VERSION 5.7 ;
  NOWIREEXTENSIONATPIN ON ;
  DIVIDERCHAR "/" ;
  BUSBITCHARS "[]" ;
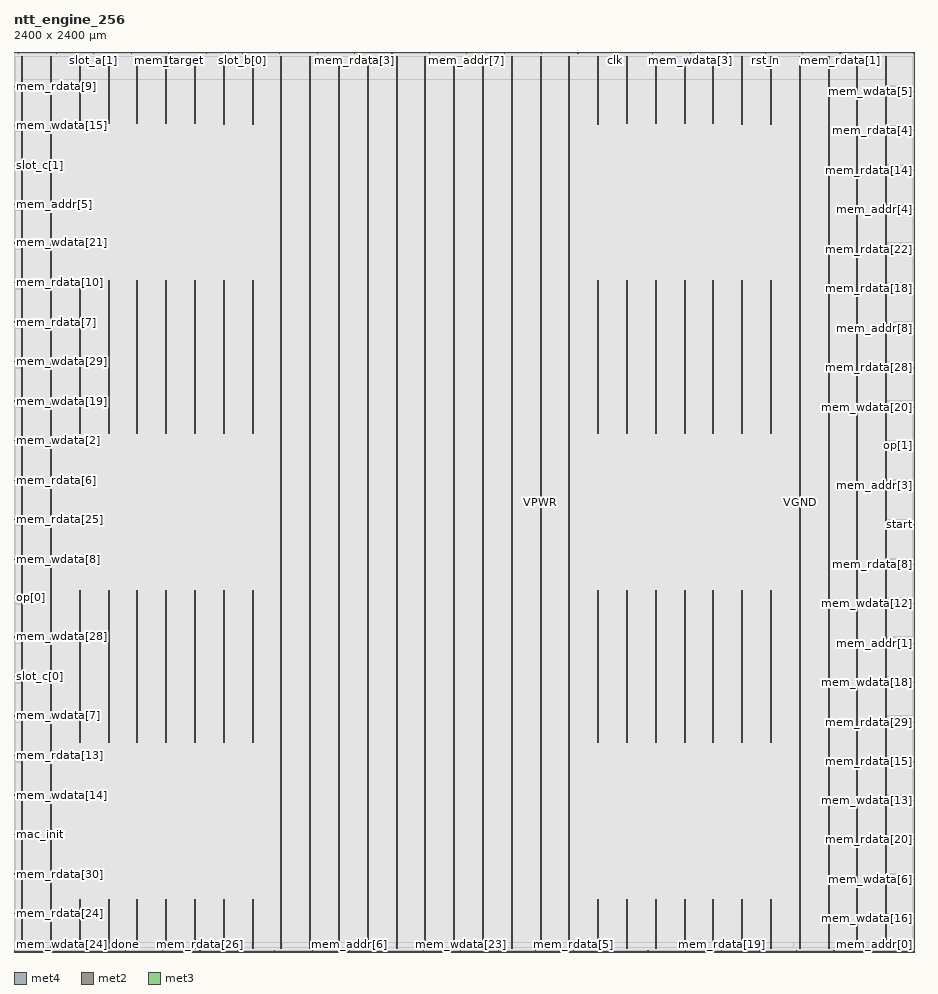
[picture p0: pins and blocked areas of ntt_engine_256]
MACRO ntt_engine_256
  CLASS BLOCK ;
  FOREIGN ntt_engine_256 ;
  ORIGIN 0.000 0.000 ;
  SIZE 2400.000 BY 2400.000 ;
  PIN VGND
    DIRECTION INOUT ;
    USE GROUND ;
    PORT
      LAYER met4 ;
        RECT 97.240 10.640 100.040 2388.400 ;
    END
    PORT
      LAYER met4 ;
        RECT 250.840 10.640 253.640 139.400 ;
    END
    PORT
      LAYER met4 ;
        RECT 250.840 557.480 253.640 964.400 ;
    END
    PORT
      LAYER met4 ;
        RECT 250.840 1382.480 253.640 1790.020 ;
    END
    PORT
      LAYER met4 ;
        RECT 250.840 2208.100 253.640 2388.400 ;
    END
    PORT
      LAYER met4 ;
        RECT 404.440 10.640 407.240 139.400 ;
    END
    PORT
      LAYER met4 ;
        RECT 404.440 557.480 407.240 964.400 ;
    END
    PORT
      LAYER met4 ;
        RECT 404.440 1382.480 407.240 1790.020 ;
    END
    PORT
      LAYER met4 ;
        RECT 404.440 2208.100 407.240 2388.400 ;
    END
    PORT
      LAYER met4 ;
        RECT 558.040 10.640 560.840 140.020 ;
    END
    PORT
      LAYER met4 ;
        RECT 558.040 557.480 560.840 965.020 ;
    END
    PORT
      LAYER met4 ;
        RECT 558.040 1382.480 560.840 1790.020 ;
    END
    PORT
      LAYER met4 ;
        RECT 558.040 2207.480 560.840 2388.400 ;
    END
    PORT
      LAYER met4 ;
        RECT 711.640 10.640 714.440 2388.400 ;
    END
    PORT
      LAYER met4 ;
        RECT 865.240 10.640 868.040 2388.400 ;
    END
    PORT
      LAYER met4 ;
        RECT 1018.840 10.640 1021.640 2388.400 ;
    END
    PORT
      LAYER met4 ;
        RECT 1172.440 10.640 1175.240 2388.400 ;
    END
    PORT
      LAYER met4 ;
        RECT 1326.040 10.640 1328.840 2388.400 ;
    END
    PORT
      LAYER met4 ;
        RECT 1479.640 10.640 1482.440 2388.400 ;
    END
    PORT
      LAYER met4 ;
        RECT 1633.240 10.640 1636.040 139.400 ;
    END
    PORT
      LAYER met4 ;
        RECT 1633.240 557.480 1636.040 964.400 ;
    END
    PORT
      LAYER met4 ;
        RECT 1633.240 1382.480 1636.040 1790.020 ;
    END
    PORT
      LAYER met4 ;
        RECT 1633.240 2208.100 1636.040 2388.400 ;
    END
    PORT
      LAYER met4 ;
        RECT 1786.840 10.640 1789.640 139.400 ;
    END
    PORT
      LAYER met4 ;
        RECT 1786.840 557.480 1789.640 964.400 ;
    END
    PORT
      LAYER met4 ;
        RECT 1786.840 1382.480 1789.640 1790.020 ;
    END
    PORT
      LAYER met4 ;
        RECT 1786.840 2208.100 1789.640 2388.400 ;
    END
    PORT
      LAYER met4 ;
        RECT 1940.440 10.640 1943.240 140.020 ;
    END
    PORT
      LAYER met4 ;
        RECT 1940.440 557.480 1943.240 965.020 ;
    END
    PORT
      LAYER met4 ;
        RECT 1940.440 1382.480 1943.240 1790.020 ;
    END
    PORT
      LAYER met4 ;
        RECT 1940.440 2207.480 1943.240 2388.400 ;
    END
    PORT
      LAYER met4 ;
        RECT 2094.040 10.640 2096.840 2388.400 ;
    END
    PORT
      LAYER met4 ;
        RECT 2247.640 10.640 2250.440 2388.400 ;
    END
  END VGND
  PIN VPWR
    DIRECTION INOUT ;
    USE POWER ;
    PORT
      LAYER met4 ;
        RECT 20.440 10.640 23.240 2388.400 ;
    END
    PORT
      LAYER met4 ;
        RECT 174.040 10.640 176.840 140.020 ;
    END
    PORT
      LAYER met4 ;
        RECT 174.040 557.360 176.840 965.020 ;
    END
    PORT
      LAYER met4 ;
        RECT 174.040 1382.480 176.840 1790.020 ;
    END
    PORT
      LAYER met4 ;
        RECT 174.040 2207.480 176.840 2388.400 ;
    END
    PORT
      LAYER met4 ;
        RECT 327.640 10.640 330.440 139.400 ;
    END
    PORT
      LAYER met4 ;
        RECT 327.640 558.100 330.440 964.400 ;
    END
    PORT
      LAYER met4 ;
        RECT 327.640 1383.100 330.440 1789.400 ;
    END
    PORT
      LAYER met4 ;
        RECT 327.640 2208.100 330.440 2388.400 ;
    END
    PORT
      LAYER met4 ;
        RECT 481.240 10.640 484.040 139.400 ;
    END
    PORT
      LAYER met4 ;
        RECT 481.240 558.100 484.040 964.400 ;
    END
    PORT
      LAYER met4 ;
        RECT 481.240 1383.100 484.040 1789.400 ;
    END
    PORT
      LAYER met4 ;
        RECT 481.240 2208.100 484.040 2388.400 ;
    END
    PORT
      LAYER met4 ;
        RECT 634.840 10.640 637.640 140.020 ;
    END
    PORT
      LAYER met4 ;
        RECT 634.840 557.360 637.640 965.020 ;
    END
    PORT
      LAYER met4 ;
        RECT 634.840 1382.480 637.640 1790.020 ;
    END
    PORT
      LAYER met4 ;
        RECT 634.840 2207.480 637.640 2388.400 ;
    END
    PORT
      LAYER met4 ;
        RECT 788.440 10.640 791.240 2388.400 ;
    END
    PORT
      LAYER met4 ;
        RECT 942.040 10.640 944.840 2388.400 ;
    END
    PORT
      LAYER met4 ;
        RECT 1095.640 10.640 1098.440 2388.400 ;
    END
    PORT
      LAYER met4 ;
        RECT 1249.240 10.640 1252.040 2388.400 ;
    END
    PORT
      LAYER met4 ;
        RECT 1402.840 10.640 1405.640 2388.400 ;
    END
    PORT
      LAYER met4 ;
        RECT 1556.440 10.640 1559.240 140.020 ;
    END
    PORT
      LAYER met4 ;
        RECT 1556.440 557.360 1559.240 965.020 ;
    END
    PORT
      LAYER met4 ;
        RECT 1556.440 1382.480 1559.240 1790.020 ;
    END
    PORT
      LAYER met4 ;
        RECT 1556.440 2207.480 1559.240 2388.400 ;
    END
    PORT
      LAYER met4 ;
        RECT 1710.040 10.640 1712.840 139.400 ;
    END
    PORT
      LAYER met4 ;
        RECT 1710.040 558.100 1712.840 964.400 ;
    END
    PORT
      LAYER met4 ;
        RECT 1710.040 1383.100 1712.840 1789.400 ;
    END
    PORT
      LAYER met4 ;
        RECT 1710.040 2208.100 1712.840 2388.400 ;
    END
    PORT
      LAYER met4 ;
        RECT 1863.640 10.640 1866.440 139.400 ;
    END
    PORT
      LAYER met4 ;
        RECT 1863.640 558.100 1866.440 964.400 ;
    END
    PORT
      LAYER met4 ;
        RECT 1863.640 1383.100 1866.440 1789.400 ;
    END
    PORT
      LAYER met4 ;
        RECT 1863.640 2208.100 1866.440 2388.400 ;
    END
    PORT
      LAYER met4 ;
        RECT 2017.240 10.640 2020.040 140.020 ;
    END
    PORT
      LAYER met4 ;
        RECT 2017.240 557.360 2020.040 965.020 ;
    END
    PORT
      LAYER met4 ;
        RECT 2017.240 1382.480 2020.040 1790.020 ;
    END
    PORT
      LAYER met4 ;
        RECT 2017.240 2207.480 2020.040 2388.400 ;
    END
    PORT
      LAYER met4 ;
        RECT 2170.840 10.640 2173.640 2388.400 ;
    END
    PORT
      LAYER met4 ;
        RECT 2324.440 10.640 2327.240 2388.400 ;
    END
  END VPWR
  PIN busy
    DIRECTION OUTPUT TRISTATE ;
    USE SIGNAL ;
    ANTENNADIFFAREA 1.782000 ;
    PORT
      LAYER met2 ;
        RECT 808.310 2396.000 808.590 2400.000 ;
    END
  END busy
  PIN clk
    DIRECTION INPUT ;
    USE SIGNAL ;
    ANTENNAGATEAREA 0.852000 ;
    ANTENNADIFFAREA 1.304100 ;
    PORT
      LAYER met2 ;
        RECT 1603.650 2396.000 1603.930 2400.000 ;
    END
  END clk
  PIN done
    DIRECTION OUTPUT TRISTATE ;
    USE SIGNAL ;
    ANTENNADIFFAREA 1.782000 ;
    PORT
      LAYER met2 ;
        RECT 296.330 0.000 296.610 4.000 ;
    END
  END done
  PIN mac_init
    DIRECTION INPUT ;
    USE SIGNAL ;
    ANTENNAGATEAREA 0.213000 ;
    PORT
      LAYER met3 ;
        RECT 0.000 312.840 4.000 313.440 ;
    END
  END mac_init
  PIN mem_addr[0]
    DIRECTION INPUT ;
    USE SIGNAL ;
    ANTENNAGATEAREA 0.495000 ;
    PORT
      LAYER met2 ;
        RECT 2386.110 0.000 2386.390 4.000 ;
    END
  END mem_addr[0]
  PIN mem_addr[1]
    DIRECTION INPUT ;
    USE SIGNAL ;
    ANTENNAGATEAREA 0.196500 ;
    PORT
      LAYER met3 ;
        RECT 2396.000 822.840 2400.000 823.440 ;
    END
  END mem_addr[1]
  PIN mem_addr[2]
    DIRECTION INPUT ;
    USE SIGNAL ;
    ANTENNAGATEAREA 0.495000 ;
    PORT
      LAYER met2 ;
        RECT 2102.750 2396.000 2103.030 2400.000 ;
    END
  END mem_addr[2]
  PIN mem_addr[3]
    DIRECTION INPUT ;
    USE SIGNAL ;
    ANTENNAGATEAREA 0.196500 ;
    PORT
      LAYER met3 ;
        RECT 2396.000 1244.440 2400.000 1245.040 ;
    END
  END mem_addr[3]
  PIN mem_addr[4]
    DIRECTION INPUT ;
    USE SIGNAL ;
    ANTENNAGATEAREA 0.495000 ;
    PORT
      LAYER met3 ;
        RECT 2396.000 1978.840 2400.000 1979.440 ;
    END
  END mem_addr[4]
  PIN mem_addr[5]
    DIRECTION INPUT ;
    USE SIGNAL ;
    ANTENNAGATEAREA 0.495000 ;
    PORT
      LAYER met3 ;
        RECT 0.000 1992.440 4.000 1993.040 ;
    END
  END mem_addr[5]
  PIN mem_addr[6]
    DIRECTION INPUT ;
    USE SIGNAL ;
    ANTENNAGATEAREA 0.495000 ;
    PORT
      LAYER met2 ;
        RECT 895.250 0.000 895.530 4.000 ;
    END
  END mem_addr[6]
  PIN mem_addr[7]
    DIRECTION INPUT ;
    USE SIGNAL ;
    ANTENNAGATEAREA 0.495000 ;
    PORT
      LAYER met2 ;
        RECT 1207.590 2396.000 1207.870 2400.000 ;
    END
  END mem_addr[7]
  PIN mem_addr[8]
    DIRECTION INPUT ;
    USE SIGNAL ;
    ANTENNAGATEAREA 0.495000 ;
    PORT
      LAYER met3 ;
        RECT 2396.000 1662.640 2400.000 1663.240 ;
    END
  END mem_addr[8]
  PIN mem_rdata[0]
    DIRECTION OUTPUT TRISTATE ;
    USE SIGNAL ;
    ANTENNADIFFAREA 1.782000 ;
    PORT
      LAYER met2 ;
        RECT 2286.290 0.000 2286.570 4.000 ;
    END
  END mem_rdata[0]
  PIN mem_rdata[10]
    DIRECTION OUTPUT TRISTATE ;
    USE SIGNAL ;
    ANTENNADIFFAREA 1.782000 ;
    PORT
      LAYER met3 ;
        RECT 0.000 1785.040 4.000 1785.640 ;
    END
  END mem_rdata[10]
  PIN mem_rdata[11]
    DIRECTION OUTPUT TRISTATE ;
    USE SIGNAL ;
    ANTENNADIFFAREA 1.782000 ;
    PORT
      LAYER met2 ;
        RECT 112.790 2396.000 113.070 2400.000 ;
    END
  END mem_rdata[11]
  PIN mem_rdata[12]
    DIRECTION OUTPUT TRISTATE ;
    USE SIGNAL ;
    ANTENNADIFFAREA 1.782000 ;
    PORT
      LAYER met2 ;
        RECT 1007.950 2396.000 1008.230 2400.000 ;
    END
  END mem_rdata[12]
  PIN mem_rdata[13]
    DIRECTION OUTPUT TRISTATE ;
    USE SIGNAL ;
    ANTENNADIFFAREA 1.782000 ;
    PORT
      LAYER met3 ;
        RECT 0.000 523.640 4.000 524.240 ;
    END
  END mem_rdata[13]
  PIN mem_rdata[14]
    DIRECTION OUTPUT TRISTATE ;
    USE SIGNAL ;
    ANTENNADIFFAREA 1.782000 ;
    PORT
      LAYER met3 ;
        RECT 2396.000 2084.240 2400.000 2084.840 ;
    END
  END mem_rdata[14]
  PIN mem_rdata[15]
    DIRECTION OUTPUT TRISTATE ;
    USE SIGNAL ;
    ANTENNADIFFAREA 1.782000 ;
    PORT
      LAYER met3 ;
        RECT 2396.000 506.640 2400.000 507.240 ;
    END
  END mem_rdata[15]
  PIN mem_rdata[16]
    DIRECTION OUTPUT TRISTATE ;
    USE SIGNAL ;
    ANTENNADIFFAREA 1.782000 ;
    PORT
      LAYER met2 ;
        RECT 1703.470 2396.000 1703.750 2400.000 ;
    END
  END mem_rdata[16]
  PIN mem_rdata[17]
    DIRECTION OUTPUT TRISTATE ;
    USE SIGNAL ;
    ANTENNADIFFAREA 1.782000 ;
    PORT
      LAYER met2 ;
        RECT 595.790 0.000 596.070 4.000 ;
    END
  END mem_rdata[17]
  PIN mem_rdata[18]
    DIRECTION OUTPUT TRISTATE ;
    USE SIGNAL ;
    ANTENNADIFFAREA 1.782000 ;
    PORT
      LAYER met3 ;
        RECT 2396.000 1768.040 2400.000 1768.640 ;
    END
  END mem_rdata[18]
  PIN mem_rdata[19]
    DIRECTION OUTPUT TRISTATE ;
    USE SIGNAL ;
    ANTENNADIFFAREA 1.782000 ;
    PORT
      LAYER met2 ;
        RECT 1887.010 0.000 1887.290 4.000 ;
    END
  END mem_rdata[19]
  PIN mem_rdata[1]
    DIRECTION OUTPUT TRISTATE ;
    USE SIGNAL ;
    ANTENNADIFFAREA 1.782000 ;
    PORT
      LAYER met2 ;
        RECT 2202.570 2396.000 2202.850 2400.000 ;
    END
  END mem_rdata[1]
  PIN mem_rdata[20]
    DIRECTION OUTPUT TRISTATE ;
    USE SIGNAL ;
    ANTENNADIFFAREA 1.782000 ;
    PORT
      LAYER met3 ;
        RECT 2396.000 299.240 2400.000 299.840 ;
    END
  END mem_rdata[20]
  PIN mem_rdata[21]
    DIRECTION OUTPUT TRISTATE ;
    USE SIGNAL ;
    ANTENNADIFFAREA 1.782000 ;
    PORT
      LAYER met2 ;
        RECT 1407.230 2396.000 1407.510 2400.000 ;
    END
  END mem_rdata[21]
  PIN mem_rdata[22]
    DIRECTION OUTPUT TRISTATE ;
    USE SIGNAL ;
    ANTENNADIFFAREA 1.782000 ;
    PORT
      LAYER met3 ;
        RECT 2396.000 1873.440 2400.000 1874.040 ;
    END
  END mem_rdata[22]
  PIN mem_rdata[23]
    DIRECTION OUTPUT TRISTATE ;
    USE SIGNAL ;
    ANTENNADIFFAREA 1.782000 ;
    PORT
      LAYER met2 ;
        RECT 12.970 2396.000 13.250 2400.000 ;
    END
  END mem_rdata[23]
  PIN mem_rdata[24]
    DIRECTION OUTPUT TRISTATE ;
    USE SIGNAL ;
    ANTENNADIFFAREA 1.782000 ;
    PORT
      LAYER met3 ;
        RECT 0.000 102.040 4.000 102.640 ;
    END
  END mem_rdata[24]
  PIN mem_rdata[25]
    DIRECTION OUTPUT TRISTATE ;
    USE SIGNAL ;
    ANTENNADIFFAREA 1.782000 ;
    PORT
      LAYER met3 ;
        RECT 0.000 1152.640 4.000 1153.240 ;
    END
  END mem_rdata[25]
  PIN mem_rdata[26]
    DIRECTION OUTPUT TRISTATE ;
    USE SIGNAL ;
    ANTENNADIFFAREA 1.782000 ;
    PORT
      LAYER met2 ;
        RECT 495.970 0.000 496.250 4.000 ;
    END
  END mem_rdata[26]
  PIN mem_rdata[27]
    DIRECTION OUTPUT TRISTATE ;
    USE SIGNAL ;
    ANTENNADIFFAREA 1.782000 ;
    PORT
      LAYER met2 ;
        RECT 1107.770 2396.000 1108.050 2400.000 ;
    END
  END mem_rdata[27]
  PIN mem_rdata[28]
    DIRECTION OUTPUT TRISTATE ;
    USE SIGNAL ;
    ANTENNADIFFAREA 1.782000 ;
    PORT
      LAYER met3 ;
        RECT 2396.000 1557.240 2400.000 1557.840 ;
    END
  END mem_rdata[28]
  PIN mem_rdata[29]
    DIRECTION OUTPUT TRISTATE ;
    USE SIGNAL ;
    ANTENNADIFFAREA 1.782000 ;
    PORT
      LAYER met3 ;
        RECT 2396.000 612.040 2400.000 612.640 ;
    END
  END mem_rdata[29]
  PIN mem_rdata[2]
    DIRECTION OUTPUT TRISTATE ;
    USE SIGNAL ;
    ANTENNADIFFAREA 1.782000 ;
    PORT
      LAYER met2 ;
        RECT 1503.830 2396.000 1504.110 2400.000 ;
    END
  END mem_rdata[2]
  PIN mem_rdata[30]
    DIRECTION OUTPUT TRISTATE ;
    USE SIGNAL ;
    ANTENNADIFFAREA 1.782000 ;
    PORT
      LAYER met3 ;
        RECT 0.000 207.440 4.000 208.040 ;
    END
  END mem_rdata[30]
  PIN mem_rdata[31]
    DIRECTION OUTPUT TRISTATE ;
    USE SIGNAL ;
    ANTENNADIFFAREA 1.782000 ;
    PORT
      LAYER met2 ;
        RECT 2186.470 0.000 2186.750 4.000 ;
    END
  END mem_rdata[31]
  PIN mem_rdata[3]
    DIRECTION OUTPUT TRISTATE ;
    USE SIGNAL ;
    ANTENNADIFFAREA 1.782000 ;
    PORT
      LAYER met2 ;
        RECT 908.130 2396.000 908.410 2400.000 ;
    END
  END mem_rdata[3]
  PIN mem_rdata[4]
    DIRECTION OUTPUT TRISTATE ;
    USE SIGNAL ;
    ANTENNADIFFAREA 1.782000 ;
    PORT
      LAYER met3 ;
        RECT 2396.000 2189.640 2400.000 2190.240 ;
    END
  END mem_rdata[4]
  PIN mem_rdata[5]
    DIRECTION OUTPUT TRISTATE ;
    USE SIGNAL ;
    ANTENNADIFFAREA 1.782000 ;
    PORT
      LAYER met2 ;
        RECT 1490.950 0.000 1491.230 4.000 ;
    END
  END mem_rdata[5]
  PIN mem_rdata[6]
    DIRECTION OUTPUT TRISTATE ;
    USE SIGNAL ;
    ANTENNADIFFAREA 1.782000 ;
    PORT
      LAYER met3 ;
        RECT 0.000 1258.040 4.000 1258.640 ;
    END
  END mem_rdata[6]
  PIN mem_rdata[7]
    DIRECTION OUTPUT TRISTATE ;
    USE SIGNAL ;
    ANTENNADIFFAREA 1.782000 ;
    PORT
      LAYER met3 ;
        RECT 0.000 1679.640 4.000 1680.240 ;
    END
  END mem_rdata[7]
  PIN mem_rdata[8]
    DIRECTION OUTPUT TRISTATE ;
    USE SIGNAL ;
    ANTENNADIFFAREA 1.782000 ;
    PORT
      LAYER met3 ;
        RECT 2396.000 1033.640 2400.000 1034.240 ;
    END
  END mem_rdata[8]
  PIN mem_rdata[9]
    DIRECTION OUTPUT TRISTATE ;
    USE SIGNAL ;
    ANTENNADIFFAREA 1.782000 ;
    PORT
      LAYER met3 ;
        RECT 0.000 2308.640 4.000 2309.240 ;
    END
  END mem_rdata[9]
  PIN mem_re
    DIRECTION INPUT ;
    USE SIGNAL ;
    ANTENNAGATEAREA 0.495000 ;
    PORT
      LAYER met2 ;
        RECT 1986.830 0.000 1987.110 4.000 ;
    END
  END mem_re
  PIN mem_rvalid
    DIRECTION OUTPUT TRISTATE ;
    USE SIGNAL ;
    ANTENNADIFFAREA 1.782000 ;
    PORT
      LAYER met2 ;
        RECT 991.850 0.000 992.130 4.000 ;
    END
  END mem_rvalid
  PIN mem_slot[0]
    DIRECTION INPUT ;
    USE SIGNAL ;
    ANTENNAGATEAREA 0.196500 ;
    PORT
      LAYER met2 ;
        RECT 1690.590 0.000 1690.870 4.000 ;
    END
  END mem_slot[0]
  PIN mem_slot[1]
    DIRECTION INPUT ;
    USE SIGNAL ;
    ANTENNAGATEAREA 0.196500 ;
    PORT
      LAYER met2 ;
        RECT 2398.990 2396.000 2399.270 2400.000 ;
    END
  END mem_slot[1]
  PIN mem_target
    DIRECTION INPUT ;
    USE SIGNAL ;
    ANTENNAGATEAREA 0.495000 ;
    PORT
      LAYER met2 ;
        RECT 412.250 2396.000 412.530 2400.000 ;
    END
  END mem_target
  PIN mem_wdata[0]
    DIRECTION INPUT ;
    USE SIGNAL ;
    ANTENNAGATEAREA 0.196500 ;
    PORT
      LAYER met2 ;
        RECT 196.510 0.000 196.790 4.000 ;
    END
  END mem_wdata[0]
  PIN mem_wdata[10]
    DIRECTION INPUT ;
    USE SIGNAL ;
    ANTENNAGATEAREA 0.495000 ;
    PORT
      LAYER met2 ;
        RECT 695.610 0.000 695.890 4.000 ;
    END
  END mem_wdata[10]
  PIN mem_wdata[11]
    DIRECTION INPUT ;
    USE SIGNAL ;
    ANTENNAGATEAREA 0.495000 ;
    PORT
      LAYER met2 ;
        RECT 2086.650 0.000 2086.930 4.000 ;
    END
  END mem_wdata[11]
  PIN mem_wdata[12]
    DIRECTION INPUT ;
    USE SIGNAL ;
    ANTENNAGATEAREA 0.126000 ;
    PORT
      LAYER met3 ;
        RECT 2396.000 928.240 2400.000 928.840 ;
    END
  END mem_wdata[12]
  PIN mem_wdata[13]
    DIRECTION INPUT ;
    USE SIGNAL ;
    ANTENNAGATEAREA 0.495000 ;
    PORT
      LAYER met3 ;
        RECT 2396.000 404.640 2400.000 405.240 ;
    END
  END mem_wdata[13]
  PIN mem_wdata[14]
    DIRECTION INPUT ;
    USE SIGNAL ;
    ANTENNAGATEAREA 0.495000 ;
    PORT
      LAYER met3 ;
        RECT 0.000 418.240 4.000 418.840 ;
    END
  END mem_wdata[14]
  PIN mem_wdata[15]
    DIRECTION INPUT ;
    USE SIGNAL ;
    ANTENNAGATEAREA 0.495000 ;
    PORT
      LAYER met3 ;
        RECT 0.000 2203.240 4.000 2203.840 ;
    END
  END mem_wdata[15]
  PIN mem_wdata[16]
    DIRECTION INPUT ;
    USE SIGNAL ;
    ANTENNAGATEAREA 0.495000 ;
    PORT
      LAYER met3 ;
        RECT 2396.000 88.440 2400.000 89.040 ;
    END
  END mem_wdata[16]
  PIN mem_wdata[17]
    DIRECTION INPUT ;
    USE SIGNAL ;
    ANTENNAGATEAREA 0.495000 ;
    PORT
      LAYER met2 ;
        RECT 512.070 2396.000 512.350 2400.000 ;
    END
  END mem_wdata[17]
  PIN mem_wdata[18]
    DIRECTION INPUT ;
    USE SIGNAL ;
    ANTENNAGATEAREA 0.126000 ;
    ANTENNADIFFAREA 0.434700 ;
    PORT
      LAYER met3 ;
        RECT 2396.000 717.440 2400.000 718.040 ;
    END
  END mem_wdata[18]
  PIN mem_wdata[19]
    DIRECTION INPUT ;
    USE SIGNAL ;
    ANTENNAGATEAREA 0.495000 ;
    PORT
      LAYER met3 ;
        RECT 0.000 1468.840 4.000 1469.440 ;
    END
  END mem_wdata[19]
  PIN mem_wdata[1]
    DIRECTION INPUT ;
    USE SIGNAL ;
    ANTENNAGATEAREA 0.495000 ;
    PORT
      LAYER met2 ;
        RECT 1790.410 0.000 1790.690 4.000 ;
    END
  END mem_wdata[1]
  PIN mem_wdata[20]
    DIRECTION INPUT ;
    USE SIGNAL ;
    ANTENNAGATEAREA 0.196500 ;
    PORT
      LAYER met3 ;
        RECT 2396.000 1451.840 2400.000 1452.440 ;
    END
  END mem_wdata[20]
  PIN mem_wdata[21]
    DIRECTION INPUT ;
    USE SIGNAL ;
    ANTENNAGATEAREA 0.495000 ;
    PORT
      LAYER met3 ;
        RECT 0.000 1890.440 4.000 1891.040 ;
    END
  END mem_wdata[21]
  PIN mem_wdata[22]
    DIRECTION INPUT ;
    USE SIGNAL ;
    ANTENNAGATEAREA 0.196500 ;
    PORT
      LAYER met2 ;
        RECT 312.430 2396.000 312.710 2400.000 ;
    END
  END mem_wdata[22]
  PIN mem_wdata[23]
    DIRECTION INPUT ;
    USE SIGNAL ;
    ANTENNAGATEAREA 0.495000 ;
    PORT
      LAYER met2 ;
        RECT 1191.490 0.000 1191.770 4.000 ;
    END
  END mem_wdata[23]
  PIN mem_wdata[24]
    DIRECTION INPUT ;
    USE SIGNAL ;
    ANTENNAGATEAREA 0.495000 ;
    PORT
      LAYER met2 ;
        RECT 0.090 0.000 0.370 4.000 ;
    END
  END mem_wdata[24]
  PIN mem_wdata[25]
    DIRECTION INPUT ;
    USE SIGNAL ;
    ANTENNAGATEAREA 0.495000 ;
    PORT
      LAYER met2 ;
        RECT 1391.130 0.000 1391.410 4.000 ;
    END
  END mem_wdata[25]
  PIN mem_wdata[26]
    DIRECTION INPUT ;
    USE SIGNAL ;
    ANTENNAGATEAREA 0.495000 ;
    PORT
      LAYER met2 ;
        RECT 708.490 2396.000 708.770 2400.000 ;
    END
  END mem_wdata[26]
  PIN mem_wdata[27]
    DIRECTION INPUT ;
    USE SIGNAL ;
    ANTENNAGATEAREA 0.495000 ;
    PORT
      LAYER met2 ;
        RECT 1307.410 2396.000 1307.690 2400.000 ;
    END
  END mem_wdata[27]
  PIN mem_wdata[28]
    DIRECTION INPUT ;
    USE SIGNAL ;
    ANTENNAGATEAREA 0.196500 ;
    PORT
      LAYER met3 ;
        RECT 0.000 839.840 4.000 840.440 ;
    END
  END mem_wdata[28]
  PIN mem_wdata[29]
    DIRECTION INPUT ;
    USE SIGNAL ;
    ANTENNAGATEAREA 0.196500 ;
    PORT
      LAYER met3 ;
        RECT 0.000 1574.240 4.000 1574.840 ;
    END
  END mem_wdata[29]
  PIN mem_wdata[2]
    DIRECTION INPUT ;
    USE SIGNAL ;
    ANTENNAGATEAREA 0.495000 ;
    PORT
      LAYER met3 ;
        RECT 0.000 1363.440 4.000 1364.040 ;
    END
  END mem_wdata[2]
  PIN mem_wdata[30]
    DIRECTION INPUT ;
    USE SIGNAL ;
    ANTENNAGATEAREA 0.495000 ;
    PORT
      LAYER met2 ;
        RECT 96.690 0.000 96.970 4.000 ;
    END
  END mem_wdata[30]
  PIN mem_wdata[31]
    DIRECTION INPUT ;
    USE SIGNAL ;
    ANTENNAGATEAREA 0.495000 ;
    PORT
      LAYER met2 ;
        RECT 2302.390 2396.000 2302.670 2400.000 ;
    END
  END mem_wdata[31]
  PIN mem_wdata[3]
    DIRECTION INPUT ;
    USE SIGNAL ;
    ANTENNAGATEAREA 0.495000 ;
    PORT
      LAYER met2 ;
        RECT 1803.290 2396.000 1803.570 2400.000 ;
    END
  END mem_wdata[3]
  PIN mem_wdata[4]
    DIRECTION INPUT ;
    USE SIGNAL ;
    ANTENNAGATEAREA 0.495000 ;
    PORT
      LAYER met2 ;
        RECT 1091.670 0.000 1091.950 4.000 ;
    END
  END mem_wdata[4]
  PIN mem_wdata[5]
    DIRECTION INPUT ;
    USE SIGNAL ;
    ANTENNAGATEAREA 0.213000 ;
    PORT
      LAYER met3 ;
        RECT 2396.000 2295.040 2400.000 2295.640 ;
    END
  END mem_wdata[5]
  PIN mem_wdata[6]
    DIRECTION INPUT ;
    USE SIGNAL ;
    ANTENNAGATEAREA 0.196500 ;
    PORT
      LAYER met3 ;
        RECT 2396.000 193.840 2400.000 194.440 ;
    END
  END mem_wdata[6]
  PIN mem_wdata[7]
    DIRECTION INPUT ;
    USE SIGNAL ;
    ANTENNAGATEAREA 0.495000 ;
    PORT
      LAYER met3 ;
        RECT 0.000 629.040 4.000 629.640 ;
    END
  END mem_wdata[7]
  PIN mem_wdata[8]
    DIRECTION INPUT ;
    USE SIGNAL ;
    ANTENNAGATEAREA 0.126000 ;
    PORT
      LAYER met3 ;
        RECT 0.000 1047.240 4.000 1047.840 ;
    END
  END mem_wdata[8]
  PIN mem_wdata[9]
    DIRECTION INPUT ;
    USE SIGNAL ;
    ANTENNAGATEAREA 0.742500 ;
    PORT
      LAYER met2 ;
        RECT 396.150 0.000 396.430 4.000 ;
    END
  END mem_wdata[9]
  PIN mem_we
    DIRECTION INPUT ;
    USE SIGNAL ;
    ANTENNAGATEAREA 0.495000 ;
    PORT
      LAYER met2 ;
        RECT 795.430 0.000 795.710 4.000 ;
    END
  END mem_we
  PIN op[0]
    DIRECTION INPUT ;
    USE SIGNAL ;
    ANTENNAGATEAREA 0.247500 ;
    PORT
      LAYER met3 ;
        RECT 0.000 945.240 4.000 945.840 ;
    END
  END op[0]
  PIN op[1]
    DIRECTION INPUT ;
    USE SIGNAL ;
    ANTENNAGATEAREA 0.495000 ;
    PORT
      LAYER met3 ;
        RECT 2396.000 1349.840 2400.000 1350.440 ;
    END
  END op[1]
  PIN op[2]
    DIRECTION INPUT ;
    USE SIGNAL ;
    ANTENNAGATEAREA 0.495000 ;
    PORT
      LAYER met2 ;
        RECT 1291.310 0.000 1291.590 4.000 ;
    END
  END op[2]
  PIN rst_n
    DIRECTION INPUT ;
    USE SIGNAL ;
    ANTENNAGATEAREA 0.196500 ;
    PORT
      LAYER met2 ;
        RECT 2002.930 2396.000 2003.210 2400.000 ;
    END
  END rst_n
  PIN slot_a[0]
    DIRECTION INPUT ;
    USE SIGNAL ;
    ANTENNAGATEAREA 0.495000 ;
    PORT
      LAYER met2 ;
        RECT 1903.110 2396.000 1903.390 2400.000 ;
    END
  END slot_a[0]
  PIN slot_a[1]
    DIRECTION INPUT ;
    USE SIGNAL ;
    ANTENNAGATEAREA 0.495000 ;
    PORT
      LAYER met2 ;
        RECT 212.610 2396.000 212.890 2400.000 ;
    END
  END slot_a[1]
  PIN slot_b[0]
    DIRECTION INPUT ;
    USE SIGNAL ;
    ANTENNAGATEAREA 0.495000 ;
    PORT
      LAYER met2 ;
        RECT 608.670 2396.000 608.950 2400.000 ;
    END
  END slot_b[0]
  PIN slot_b[1]
    DIRECTION INPUT ;
    USE SIGNAL ;
    ANTENNAGATEAREA 0.495000 ;
    PORT
      LAYER met2 ;
        RECT 1590.770 0.000 1591.050 4.000 ;
    END
  END slot_b[1]
  PIN slot_c[0]
    DIRECTION INPUT ;
    USE SIGNAL ;
    ANTENNAGATEAREA 0.495000 ;
    PORT
      LAYER met3 ;
        RECT 0.000 734.440 4.000 735.040 ;
    END
  END slot_c[0]
  PIN slot_c[1]
    DIRECTION INPUT ;
    USE SIGNAL ;
    ANTENNAGATEAREA 0.495000 ;
    PORT
      LAYER met3 ;
        RECT 0.000 2097.840 4.000 2098.440 ;
    END
  END slot_c[1]
  PIN start
    DIRECTION INPUT ;
    USE SIGNAL ;
    ANTENNAGATEAREA 0.495000 ;
    PORT
      LAYER met3 ;
        RECT 2396.000 1139.040 2400.000 1139.640 ;
    END
  END start
  OBS
      LAYER li1 ;
        RECT 5.520 10.795 2394.300 2388.245 ;
      LAYER met1 ;
        RECT 0.070 10.640 2399.290 2388.400 ;
      LAYER met2 ;
        RECT 0.100 2395.720 12.690 2396.730 ;
        RECT 13.530 2395.720 112.510 2396.730 ;
        RECT 113.350 2395.720 212.330 2396.730 ;
        RECT 213.170 2395.720 312.150 2396.730 ;
        RECT 312.990 2395.720 411.970 2396.730 ;
        RECT 412.810 2395.720 511.790 2396.730 ;
        RECT 512.630 2395.720 608.390 2396.730 ;
        RECT 609.230 2395.720 708.210 2396.730 ;
        RECT 709.050 2395.720 808.030 2396.730 ;
        RECT 808.870 2395.720 907.850 2396.730 ;
        RECT 908.690 2395.720 1007.670 2396.730 ;
        RECT 1008.510 2395.720 1107.490 2396.730 ;
        RECT 1108.330 2395.720 1207.310 2396.730 ;
        RECT 1208.150 2395.720 1307.130 2396.730 ;
        RECT 1307.970 2395.720 1406.950 2396.730 ;
        RECT 1407.790 2395.720 1503.550 2396.730 ;
        RECT 1504.390 2395.720 1603.370 2396.730 ;
        RECT 1604.210 2395.720 1703.190 2396.730 ;
        RECT 1704.030 2395.720 1803.010 2396.730 ;
        RECT 1803.850 2395.720 1902.830 2396.730 ;
        RECT 1903.670 2395.720 2002.650 2396.730 ;
        RECT 2003.490 2395.720 2102.470 2396.730 ;
        RECT 2103.310 2395.720 2202.290 2396.730 ;
        RECT 2203.130 2395.720 2302.110 2396.730 ;
        RECT 2302.950 2395.720 2398.710 2396.730 ;
        RECT 0.100 4.280 2399.260 2395.720 ;
        RECT 0.650 3.670 96.410 4.280 ;
        RECT 97.250 3.670 196.230 4.280 ;
        RECT 197.070 3.670 296.050 4.280 ;
        RECT 296.890 3.670 395.870 4.280 ;
        RECT 396.710 3.670 495.690 4.280 ;
        RECT 496.530 3.670 595.510 4.280 ;
        RECT 596.350 3.670 695.330 4.280 ;
        RECT 696.170 3.670 795.150 4.280 ;
        RECT 795.990 3.670 894.970 4.280 ;
        RECT 895.810 3.670 991.570 4.280 ;
        RECT 992.410 3.670 1091.390 4.280 ;
        RECT 1092.230 3.670 1191.210 4.280 ;
        RECT 1192.050 3.670 1291.030 4.280 ;
        RECT 1291.870 3.670 1390.850 4.280 ;
        RECT 1391.690 3.670 1490.670 4.280 ;
        RECT 1491.510 3.670 1590.490 4.280 ;
        RECT 1591.330 3.670 1690.310 4.280 ;
        RECT 1691.150 3.670 1790.130 4.280 ;
        RECT 1790.970 3.670 1886.730 4.280 ;
        RECT 1887.570 3.670 1986.550 4.280 ;
        RECT 1987.390 3.670 2086.370 4.280 ;
        RECT 2087.210 3.670 2186.190 4.280 ;
        RECT 2187.030 3.670 2286.010 4.280 ;
        RECT 2286.850 3.670 2385.830 4.280 ;
        RECT 2386.670 3.670 2399.260 4.280 ;
      LAYER met3 ;
        RECT 3.990 2309.640 2396.000 2388.325 ;
        RECT 4.400 2308.240 2396.000 2309.640 ;
        RECT 3.990 2296.040 2396.000 2308.240 ;
        RECT 3.990 2294.640 2395.600 2296.040 ;
        RECT 3.990 2204.240 2396.000 2294.640 ;
        RECT 4.400 2202.840 2396.000 2204.240 ;
        RECT 3.990 2190.640 2396.000 2202.840 ;
        RECT 3.990 2189.240 2395.600 2190.640 ;
        RECT 3.990 2098.840 2396.000 2189.240 ;
        RECT 4.400 2097.440 2396.000 2098.840 ;
        RECT 3.990 2085.240 2396.000 2097.440 ;
        RECT 3.990 2083.840 2395.600 2085.240 ;
        RECT 3.990 1993.440 2396.000 2083.840 ;
        RECT 4.400 1992.040 2396.000 1993.440 ;
        RECT 3.990 1979.840 2396.000 1992.040 ;
        RECT 3.990 1978.440 2395.600 1979.840 ;
        RECT 3.990 1891.440 2396.000 1978.440 ;
        RECT 4.400 1890.040 2396.000 1891.440 ;
        RECT 3.990 1874.440 2396.000 1890.040 ;
        RECT 3.990 1873.040 2395.600 1874.440 ;
        RECT 3.990 1786.040 2396.000 1873.040 ;
        RECT 4.400 1784.640 2396.000 1786.040 ;
        RECT 3.990 1769.040 2396.000 1784.640 ;
        RECT 3.990 1767.640 2395.600 1769.040 ;
        RECT 3.990 1680.640 2396.000 1767.640 ;
        RECT 4.400 1679.240 2396.000 1680.640 ;
        RECT 3.990 1663.640 2396.000 1679.240 ;
        RECT 3.990 1662.240 2395.600 1663.640 ;
        RECT 3.990 1575.240 2396.000 1662.240 ;
        RECT 4.400 1573.840 2396.000 1575.240 ;
        RECT 3.990 1558.240 2396.000 1573.840 ;
        RECT 3.990 1556.840 2395.600 1558.240 ;
        RECT 3.990 1469.840 2396.000 1556.840 ;
        RECT 4.400 1468.440 2396.000 1469.840 ;
        RECT 3.990 1452.840 2396.000 1468.440 ;
        RECT 3.990 1451.440 2395.600 1452.840 ;
        RECT 3.990 1364.440 2396.000 1451.440 ;
        RECT 4.400 1363.040 2396.000 1364.440 ;
        RECT 3.990 1350.840 2396.000 1363.040 ;
        RECT 3.990 1349.440 2395.600 1350.840 ;
        RECT 3.990 1259.040 2396.000 1349.440 ;
        RECT 4.400 1257.640 2396.000 1259.040 ;
        RECT 3.990 1245.440 2396.000 1257.640 ;
        RECT 3.990 1244.040 2395.600 1245.440 ;
        RECT 3.990 1153.640 2396.000 1244.040 ;
        RECT 4.400 1152.240 2396.000 1153.640 ;
        RECT 3.990 1140.040 2396.000 1152.240 ;
        RECT 3.990 1138.640 2395.600 1140.040 ;
        RECT 3.990 1048.240 2396.000 1138.640 ;
        RECT 4.400 1046.840 2396.000 1048.240 ;
        RECT 3.990 1034.640 2396.000 1046.840 ;
        RECT 3.990 1033.240 2395.600 1034.640 ;
        RECT 3.990 946.240 2396.000 1033.240 ;
        RECT 4.400 944.840 2396.000 946.240 ;
        RECT 3.990 929.240 2396.000 944.840 ;
        RECT 3.990 927.840 2395.600 929.240 ;
        RECT 3.990 840.840 2396.000 927.840 ;
        RECT 4.400 839.440 2396.000 840.840 ;
        RECT 3.990 823.840 2396.000 839.440 ;
        RECT 3.990 822.440 2395.600 823.840 ;
        RECT 3.990 735.440 2396.000 822.440 ;
        RECT 4.400 734.040 2396.000 735.440 ;
        RECT 3.990 718.440 2396.000 734.040 ;
        RECT 3.990 717.040 2395.600 718.440 ;
        RECT 3.990 630.040 2396.000 717.040 ;
        RECT 4.400 628.640 2396.000 630.040 ;
        RECT 3.990 613.040 2396.000 628.640 ;
        RECT 3.990 611.640 2395.600 613.040 ;
        RECT 3.990 524.640 2396.000 611.640 ;
        RECT 4.400 523.240 2396.000 524.640 ;
        RECT 3.990 507.640 2396.000 523.240 ;
        RECT 3.990 506.240 2395.600 507.640 ;
        RECT 3.990 419.240 2396.000 506.240 ;
        RECT 4.400 417.840 2396.000 419.240 ;
        RECT 3.990 405.640 2396.000 417.840 ;
        RECT 3.990 404.240 2395.600 405.640 ;
        RECT 3.990 313.840 2396.000 404.240 ;
        RECT 4.400 312.440 2396.000 313.840 ;
        RECT 3.990 300.240 2396.000 312.440 ;
        RECT 3.990 298.840 2395.600 300.240 ;
        RECT 3.990 208.440 2396.000 298.840 ;
        RECT 4.400 207.040 2396.000 208.440 ;
        RECT 3.990 194.840 2396.000 207.040 ;
        RECT 3.990 193.440 2395.600 194.840 ;
        RECT 3.990 103.040 2396.000 193.440 ;
        RECT 4.400 101.640 2396.000 103.040 ;
        RECT 3.990 89.440 2396.000 101.640 ;
        RECT 3.990 88.040 2395.600 89.440 ;
        RECT 3.990 10.715 2396.000 88.040 ;
      LAYER met4 ;
        RECT 23.790 11.735 96.840 2298.225 ;
        RECT 100.440 2207.080 173.640 2298.225 ;
        RECT 177.240 2207.700 250.440 2298.225 ;
        RECT 254.040 2207.700 327.240 2298.225 ;
        RECT 330.840 2207.700 404.040 2298.225 ;
        RECT 407.640 2207.700 480.840 2298.225 ;
        RECT 484.440 2207.700 557.640 2298.225 ;
        RECT 177.240 2207.080 557.640 2207.700 ;
        RECT 561.240 2207.080 634.440 2298.225 ;
        RECT 638.040 2207.080 711.240 2298.225 ;
        RECT 100.440 1790.420 711.240 2207.080 ;
        RECT 100.440 1382.080 173.640 1790.420 ;
        RECT 177.240 1382.080 250.440 1790.420 ;
        RECT 254.040 1789.800 404.040 1790.420 ;
        RECT 254.040 1382.700 327.240 1789.800 ;
        RECT 330.840 1382.700 404.040 1789.800 ;
        RECT 254.040 1382.080 404.040 1382.700 ;
        RECT 407.640 1789.800 557.640 1790.420 ;
        RECT 407.640 1382.700 480.840 1789.800 ;
        RECT 484.440 1382.700 557.640 1789.800 ;
        RECT 407.640 1382.080 557.640 1382.700 ;
        RECT 561.240 1382.080 634.440 1790.420 ;
        RECT 638.040 1382.080 711.240 1790.420 ;
        RECT 100.440 965.420 711.240 1382.080 ;
        RECT 100.440 556.960 173.640 965.420 ;
        RECT 177.240 964.800 557.640 965.420 ;
        RECT 177.240 557.080 250.440 964.800 ;
        RECT 254.040 557.700 327.240 964.800 ;
        RECT 330.840 557.700 404.040 964.800 ;
        RECT 254.040 557.080 404.040 557.700 ;
        RECT 407.640 557.700 480.840 964.800 ;
        RECT 484.440 557.700 557.640 964.800 ;
        RECT 407.640 557.080 557.640 557.700 ;
        RECT 561.240 557.080 634.440 965.420 ;
        RECT 177.240 556.960 634.440 557.080 ;
        RECT 638.040 556.960 711.240 965.420 ;
        RECT 100.440 140.420 711.240 556.960 ;
        RECT 100.440 11.735 173.640 140.420 ;
        RECT 177.240 139.800 557.640 140.420 ;
        RECT 177.240 11.735 250.440 139.800 ;
        RECT 254.040 11.735 327.240 139.800 ;
        RECT 330.840 11.735 404.040 139.800 ;
        RECT 407.640 11.735 480.840 139.800 ;
        RECT 484.440 11.735 557.640 139.800 ;
        RECT 561.240 11.735 634.440 140.420 ;
        RECT 638.040 11.735 711.240 140.420 ;
        RECT 714.840 11.735 788.040 2298.225 ;
        RECT 791.640 11.735 864.840 2298.225 ;
        RECT 868.440 11.735 941.640 2298.225 ;
        RECT 945.240 11.735 1018.440 2298.225 ;
        RECT 1022.040 11.735 1095.240 2298.225 ;
        RECT 1098.840 11.735 1172.040 2298.225 ;
        RECT 1175.640 11.735 1248.840 2298.225 ;
        RECT 1252.440 11.735 1325.640 2298.225 ;
        RECT 1329.240 11.735 1402.440 2298.225 ;
        RECT 1406.040 11.735 1479.240 2298.225 ;
        RECT 1482.840 2207.080 1556.040 2298.225 ;
        RECT 1559.640 2207.700 1632.840 2298.225 ;
        RECT 1636.440 2207.700 1709.640 2298.225 ;
        RECT 1713.240 2207.700 1786.440 2298.225 ;
        RECT 1790.040 2207.700 1863.240 2298.225 ;
        RECT 1866.840 2207.700 1940.040 2298.225 ;
        RECT 1559.640 2207.080 1940.040 2207.700 ;
        RECT 1943.640 2207.080 2016.840 2298.225 ;
        RECT 2020.440 2207.080 2077.490 2298.225 ;
        RECT 1482.840 1790.420 2077.490 2207.080 ;
        RECT 1482.840 1382.080 1556.040 1790.420 ;
        RECT 1559.640 1382.080 1632.840 1790.420 ;
        RECT 1636.440 1789.800 1786.440 1790.420 ;
        RECT 1636.440 1382.700 1709.640 1789.800 ;
        RECT 1713.240 1382.700 1786.440 1789.800 ;
        RECT 1636.440 1382.080 1786.440 1382.700 ;
        RECT 1790.040 1789.800 1940.040 1790.420 ;
        RECT 1790.040 1382.700 1863.240 1789.800 ;
        RECT 1866.840 1382.700 1940.040 1789.800 ;
        RECT 1790.040 1382.080 1940.040 1382.700 ;
        RECT 1943.640 1382.080 2016.840 1790.420 ;
        RECT 2020.440 1382.080 2077.490 1790.420 ;
        RECT 1482.840 965.420 2077.490 1382.080 ;
        RECT 1482.840 556.960 1556.040 965.420 ;
        RECT 1559.640 964.800 1940.040 965.420 ;
        RECT 1559.640 557.080 1632.840 964.800 ;
        RECT 1636.440 557.700 1709.640 964.800 ;
        RECT 1713.240 557.700 1786.440 964.800 ;
        RECT 1636.440 557.080 1786.440 557.700 ;
        RECT 1790.040 557.700 1863.240 964.800 ;
        RECT 1866.840 557.700 1940.040 964.800 ;
        RECT 1790.040 557.080 1940.040 557.700 ;
        RECT 1943.640 557.080 2016.840 965.420 ;
        RECT 1559.640 556.960 2016.840 557.080 ;
        RECT 2020.440 556.960 2077.490 965.420 ;
        RECT 1482.840 140.420 2077.490 556.960 ;
        RECT 1482.840 11.735 1556.040 140.420 ;
        RECT 1559.640 139.800 1940.040 140.420 ;
        RECT 1559.640 11.735 1632.840 139.800 ;
        RECT 1636.440 11.735 1709.640 139.800 ;
        RECT 1713.240 11.735 1786.440 139.800 ;
        RECT 1790.040 11.735 1863.240 139.800 ;
        RECT 1866.840 11.735 1940.040 139.800 ;
        RECT 1943.640 11.735 2016.840 140.420 ;
        RECT 2020.440 11.735 2077.490 140.420 ;
      LAYER met5 ;
        RECT 20.440 26.130 2327.240 2326.630 ;
  END
END ntt_engine_256
END LIBRARY

